VERSION 5.7 ;
  NOWIREEXTENSIONATPIN ON ;
  DIVIDERCHAR "/" ;
  BUSBITCHARS "[]" ;
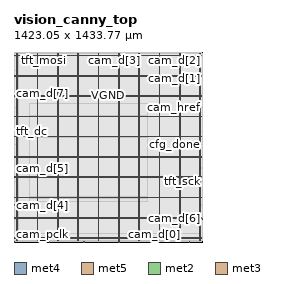
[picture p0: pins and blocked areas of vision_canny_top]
MACRO vision_canny_top
  CLASS BLOCK ;
  FOREIGN vision_canny_top ;
  ORIGIN 0.000 0.000 ;
  SIZE 1423.045 BY 1433.765 ;
  PIN VGND
    DIRECTION INOUT ;
    USE GROUND ;
    PORT
      LAYER met4 ;
        RECT 24.340 10.640 25.940 1422.800 ;
    END
    PORT
      LAYER met4 ;
        RECT 177.940 10.640 179.540 1422.800 ;
    END
    PORT
      LAYER met4 ;
        RECT 331.540 10.640 333.140 1422.800 ;
    END
    PORT
      LAYER met4 ;
        RECT 485.140 10.640 486.740 1422.800 ;
    END
    PORT
      LAYER met4 ;
        RECT 638.740 10.640 640.340 1422.800 ;
    END
    PORT
      LAYER met4 ;
        RECT 792.340 10.640 793.940 1422.800 ;
    END
    PORT
      LAYER met4 ;
        RECT 945.940 10.640 947.540 1422.800 ;
    END
    PORT
      LAYER met4 ;
        RECT 1099.540 10.640 1101.140 1422.800 ;
    END
    PORT
      LAYER met4 ;
        RECT 1253.140 10.640 1254.740 1422.800 ;
    END
    PORT
      LAYER met4 ;
        RECT 1406.740 10.640 1408.340 1422.800 ;
    END
    PORT
      LAYER met5 ;
        RECT 5.280 30.030 1417.500 31.630 ;
    END
    PORT
      LAYER met5 ;
        RECT 5.280 183.210 1417.500 184.810 ;
    END
    PORT
      LAYER met5 ;
        RECT 5.280 336.390 1417.500 337.990 ;
    END
    PORT
      LAYER met5 ;
        RECT 5.280 489.570 1417.500 491.170 ;
    END
    PORT
      LAYER met5 ;
        RECT 5.280 642.750 1417.500 644.350 ;
    END
    PORT
      LAYER met5 ;
        RECT 5.280 795.930 1417.500 797.530 ;
    END
    PORT
      LAYER met5 ;
        RECT 5.280 949.110 1417.500 950.710 ;
    END
    PORT
      LAYER met5 ;
        RECT 5.280 1102.290 1417.500 1103.890 ;
    END
    PORT
      LAYER met5 ;
        RECT 5.280 1255.470 1417.500 1257.070 ;
    END
    PORT
      LAYER met5 ;
        RECT 5.280 1408.650 1417.500 1410.250 ;
    END
  END VGND
  PIN VPWR
    DIRECTION INOUT ;
    USE POWER ;
    PORT
      LAYER met4 ;
        RECT 21.040 10.640 22.640 1422.800 ;
    END
    PORT
      LAYER met4 ;
        RECT 174.640 10.640 176.240 1422.800 ;
    END
    PORT
      LAYER met4 ;
        RECT 328.240 10.640 329.840 1422.800 ;
    END
    PORT
      LAYER met4 ;
        RECT 481.840 10.640 483.440 1422.800 ;
    END
    PORT
      LAYER met4 ;
        RECT 635.440 10.640 637.040 1422.800 ;
    END
    PORT
      LAYER met4 ;
        RECT 789.040 10.640 790.640 1422.800 ;
    END
    PORT
      LAYER met4 ;
        RECT 942.640 10.640 944.240 1422.800 ;
    END
    PORT
      LAYER met4 ;
        RECT 1096.240 10.640 1097.840 1422.800 ;
    END
    PORT
      LAYER met4 ;
        RECT 1249.840 10.640 1251.440 1422.800 ;
    END
    PORT
      LAYER met4 ;
        RECT 1403.440 10.640 1405.040 1422.800 ;
    END
    PORT
      LAYER met5 ;
        RECT 5.280 26.730 1417.500 28.330 ;
    END
    PORT
      LAYER met5 ;
        RECT 5.280 179.910 1417.500 181.510 ;
    END
    PORT
      LAYER met5 ;
        RECT 5.280 333.090 1417.500 334.690 ;
    END
    PORT
      LAYER met5 ;
        RECT 5.280 486.270 1417.500 487.870 ;
    END
    PORT
      LAYER met5 ;
        RECT 5.280 639.450 1417.500 641.050 ;
    END
    PORT
      LAYER met5 ;
        RECT 5.280 792.630 1417.500 794.230 ;
    END
    PORT
      LAYER met5 ;
        RECT 5.280 945.810 1417.500 947.410 ;
    END
    PORT
      LAYER met5 ;
        RECT 5.280 1098.990 1417.500 1100.590 ;
    END
    PORT
      LAYER met5 ;
        RECT 5.280 1252.170 1417.500 1253.770 ;
    END
    PORT
      LAYER met5 ;
        RECT 5.280 1405.350 1417.500 1406.950 ;
    END
  END VPWR
  PIN cam_d[0]
    DIRECTION INPUT ;
    USE SIGNAL ;
    ANTENNAGATEAREA 0.426000 ;
    PORT
      LAYER met2 ;
        RECT 1059.470 0.000 1059.750 4.000 ;
    END
  END cam_d[0]
  PIN cam_d[1]
    DIRECTION INPUT ;
    USE SIGNAL ;
    ANTENNAGATEAREA 0.213000 ;
    PORT
      LAYER met3 ;
        RECT 1419.045 1292.040 1423.045 1292.640 ;
    END
  END cam_d[1]
  PIN cam_d[2]
    DIRECTION INPUT ;
    USE SIGNAL ;
    ANTENNAGATEAREA 0.213000 ;
    PORT
      LAYER met2 ;
        RECT 1288.090 1429.765 1288.370 1433.765 ;
    END
  END cam_d[2]
  PIN cam_d[3]
    DIRECTION INPUT ;
    USE SIGNAL ;
    ANTENNAGATEAREA 0.247500 ;
    PORT
      LAYER met2 ;
        RECT 760.010 1429.765 760.290 1433.765 ;
    END
  END cam_d[3]
  PIN cam_d[4]
    DIRECTION INPUT ;
    USE SIGNAL ;
    ANTENNAGATEAREA 0.990000 ;
    PORT
      LAYER met3 ;
        RECT 0.000 278.840 4.000 279.440 ;
    END
  END cam_d[4]
  PIN cam_d[5]
    DIRECTION INPUT ;
    USE SIGNAL ;
    ANTENNAGATEAREA 0.852000 ;
    PORT
      LAYER met3 ;
        RECT 0.000 557.640 4.000 558.240 ;
    END
  END cam_d[5]
  PIN cam_d[6]
    DIRECTION INPUT ;
    USE SIGNAL ;
    ANTENNAGATEAREA 0.742500 ;
    PORT
      LAYER met3 ;
        RECT 1419.045 173.440 1423.045 174.040 ;
    END
  END cam_d[6]
  PIN cam_d[7]
    DIRECTION INPUT ;
    USE SIGNAL ;
    ANTENNAGATEAREA 0.742500 ;
    PORT
      LAYER met3 ;
        RECT 0.000 1118.640 4.000 1119.240 ;
    END
  END cam_d[7]
  PIN cam_href
    DIRECTION INPUT ;
    USE SIGNAL ;
    ANTENNAGATEAREA 0.247500 ;
    PORT
      LAYER met3 ;
        RECT 1419.045 1013.240 1423.045 1013.840 ;
    END
  END cam_href
  PIN cam_pclk
    DIRECTION INPUT ;
    USE SIGNAL ;
    ANTENNAGATEAREA 1.286700 ;
    ANTENNADIFFAREA 0.434700 ;
    PORT
      LAYER met2 ;
        RECT 0.090 0.000 0.370 4.000 ;
    END
  END cam_pclk
  PIN cam_scl
    DIRECTION OUTPUT TRISTATE ;
    USE SIGNAL ;
    ANTENNADIFFAREA 0.340600 ;
    PORT
      LAYER met2 ;
        RECT 264.130 0.000 264.410 4.000 ;
    END
  END cam_scl
  PIN cam_sda_o
    DIRECTION OUTPUT TRISTATE ;
    USE SIGNAL ;
    PORT
      LAYER met2 ;
        RECT 1323.510 0.000 1323.790 4.000 ;
    END
  END cam_sda_o
  PIN cam_sda_oe
    DIRECTION OUTPUT TRISTATE ;
    USE SIGNAL ;
    ANTENNADIFFAREA 0.340600 ;
    PORT
      LAYER met2 ;
        RECT 528.170 0.000 528.450 4.000 ;
    END
  END cam_sda_oe
  PIN cam_xclk
    DIRECTION OUTPUT TRISTATE ;
    USE SIGNAL ;
    ANTENNADIFFAREA 0.340600 ;
    PORT
      LAYER met2 ;
        RECT 492.750 1429.765 493.030 1433.765 ;
    END
  END cam_xclk
  PIN cfg_done
    DIRECTION OUTPUT TRISTATE ;
    USE SIGNAL ;
    ANTENNADIFFAREA 0.340600 ;
    PORT
      LAYER met3 ;
        RECT 1419.045 734.440 1423.045 735.040 ;
    END
  END cfg_done
  PIN clk
    DIRECTION INPUT ;
    USE SIGNAL ;
    ANTENNAGATEAREA 1.721400 ;
    ANTENNADIFFAREA 0.869400 ;
    PORT
      LAYER met3 ;
        RECT 0.000 1397.440 4.000 1398.040 ;
    END
  END clk
  PIN rst_n
    DIRECTION INPUT ;
    USE SIGNAL ;
    ANTENNAGATEAREA 0.852000 ;
    PORT
      LAYER met2 ;
        RECT 1024.050 1429.765 1024.330 1433.765 ;
    END
  END rst_n
  PIN tft_cs
    DIRECTION OUTPUT TRISTATE ;
    USE SIGNAL ;
    ANTENNADIFFAREA 0.340600 ;
    PORT
      LAYER met2 ;
        RECT 792.210 0.000 792.490 4.000 ;
    END
  END tft_cs
  PIN tft_dc
    DIRECTION OUTPUT TRISTATE ;
    USE SIGNAL ;
    ANTENNADIFFAREA 0.340600 ;
    PORT
      LAYER met3 ;
        RECT 0.000 836.440 4.000 837.040 ;
    END
  END tft_dc
  PIN tft_mosi
    DIRECTION OUTPUT TRISTATE ;
    USE SIGNAL ;
    ANTENNADIFFAREA 0.340600 ;
    PORT
      LAYER met2 ;
        RECT 228.710 1429.765 228.990 1433.765 ;
    END
  END tft_mosi
  PIN tft_sck
    DIRECTION OUTPUT TRISTATE ;
    USE SIGNAL ;
    ANTENNADIFFAREA 0.340600 ;
    PORT
      LAYER met3 ;
        RECT 1419.045 455.640 1423.045 456.240 ;
    END
  END tft_sck
  OBS
      LAYER li1 ;
        RECT 5.520 10.795 1417.260 1422.645 ;
      LAYER met1 ;
        RECT 4.670 10.640 1417.560 1422.800 ;
      LAYER met2 ;
        RECT 0.090 1429.485 228.430 1430.450 ;
        RECT 229.270 1429.485 492.470 1430.450 ;
        RECT 493.310 1429.485 759.730 1430.450 ;
        RECT 760.570 1429.485 1023.770 1430.450 ;
        RECT 1024.610 1429.485 1287.810 1430.450 ;
        RECT 1288.650 1429.485 1417.170 1430.450 ;
        RECT 0.090 4.280 1417.170 1429.485 ;
        RECT 0.650 4.000 263.850 4.280 ;
        RECT 264.690 4.000 527.890 4.280 ;
        RECT 528.730 4.000 791.930 4.280 ;
        RECT 792.770 4.000 1059.190 4.280 ;
        RECT 1060.030 4.000 1323.230 4.280 ;
        RECT 1324.070 4.000 1417.170 4.280 ;
      LAYER met3 ;
        RECT 0.065 1398.440 1419.045 1422.725 ;
        RECT 4.400 1397.040 1419.045 1398.440 ;
        RECT 0.065 1293.040 1419.045 1397.040 ;
        RECT 0.065 1291.640 1418.645 1293.040 ;
        RECT 0.065 1119.640 1419.045 1291.640 ;
        RECT 4.400 1118.240 1419.045 1119.640 ;
        RECT 0.065 1014.240 1419.045 1118.240 ;
        RECT 0.065 1012.840 1418.645 1014.240 ;
        RECT 0.065 837.440 1419.045 1012.840 ;
        RECT 4.400 836.040 1419.045 837.440 ;
        RECT 0.065 735.440 1419.045 836.040 ;
        RECT 0.065 734.040 1418.645 735.440 ;
        RECT 0.065 558.640 1419.045 734.040 ;
        RECT 4.400 557.240 1419.045 558.640 ;
        RECT 0.065 456.640 1419.045 557.240 ;
        RECT 0.065 455.240 1418.645 456.640 ;
        RECT 0.065 279.840 1419.045 455.240 ;
        RECT 4.400 278.440 1419.045 279.840 ;
        RECT 0.065 174.440 1419.045 278.440 ;
        RECT 0.065 173.040 1418.645 174.440 ;
        RECT 0.065 10.715 1419.045 173.040 ;
      LAYER met4 ;
        RECT 33.415 61.375 174.240 1421.025 ;
        RECT 176.640 61.375 177.540 1421.025 ;
        RECT 179.940 61.375 327.840 1421.025 ;
        RECT 330.240 61.375 331.140 1421.025 ;
        RECT 333.540 61.375 481.440 1421.025 ;
        RECT 483.840 61.375 484.740 1421.025 ;
        RECT 487.140 61.375 635.040 1421.025 ;
        RECT 637.440 61.375 638.340 1421.025 ;
        RECT 640.740 61.375 788.640 1421.025 ;
        RECT 791.040 61.375 791.940 1421.025 ;
        RECT 794.340 61.375 942.240 1421.025 ;
        RECT 944.640 61.375 945.540 1421.025 ;
        RECT 947.940 61.375 1095.840 1421.025 ;
        RECT 1098.240 61.375 1099.140 1421.025 ;
        RECT 1101.540 61.375 1249.440 1421.025 ;
        RECT 1251.840 61.375 1252.740 1421.025 ;
        RECT 1255.140 61.375 1398.105 1421.025 ;
      LAYER met5 ;
        RECT 116.500 952.310 1008.660 1046.300 ;
        RECT 116.500 799.130 1008.660 944.210 ;
        RECT 116.500 645.950 1008.660 791.030 ;
        RECT 116.500 492.770 1008.660 637.850 ;
        RECT 116.500 339.590 1008.660 484.670 ;
        RECT 116.500 306.900 1008.660 331.490 ;
  END
END vision_canny_top
END LIBRARY

